VERSION 5.8 ;
BUSBITCHARS "[]" ;

UNITS
  DATABASE MICRONS 2000 ;
END UNITS

PROPERTYDEFINITIONS
  MACRO expanded_util REAL ;
END PROPERTYDEFINITIONS

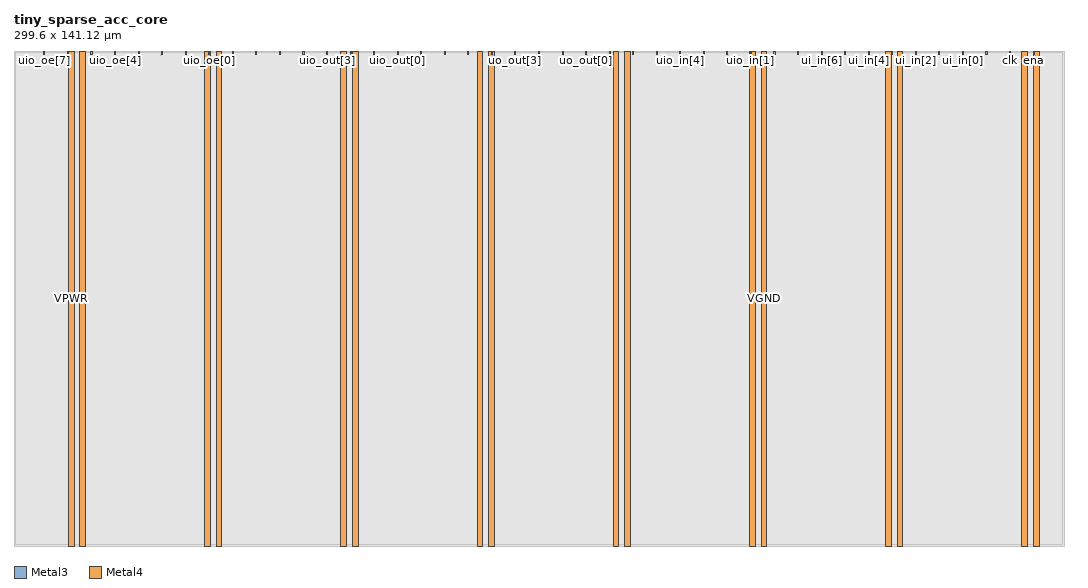
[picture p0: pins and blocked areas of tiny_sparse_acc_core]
MACRO tiny_sparse_acc_core
  CLASS BLOCK ;
  ORIGIN 0 0 ;
  SIZE 299.6 BY 141.12 ;
  SYMMETRY X Y ;
  PIN ui_in[7]
    DIRECTION INPUT ;
    USE SIGNAL ;
    PORT
      LAYER Metal3 ;
        RECT 223.57 140.12 223.87 141.12 ;
    END
  END ui_in[7]
  PIN ui_in[6]
    DIRECTION INPUT ;
    USE SIGNAL ;
    PORT
      LAYER Metal3 ;
        RECT 230.29 140.12 230.59 141.12 ;
    END
  END ui_in[6]
  PIN ui_in[5]
    DIRECTION INPUT ;
    USE SIGNAL ;
    PORT
      LAYER Metal3 ;
        RECT 237.01 140.12 237.31 141.12 ;
    END
  END ui_in[5]
  PIN ui_in[4]
    DIRECTION INPUT ;
    USE SIGNAL ;
    PORT
      LAYER Metal3 ;
        RECT 243.73 140.12 244.03 141.12 ;
    END
  END ui_in[4]
  PIN ui_in[3]
    DIRECTION INPUT ;
    USE SIGNAL ;
    PORT
      LAYER Metal3 ;
        RECT 250.45 140.12 250.75 141.12 ;
    END
  END ui_in[3]
  PIN ui_in[2]
    DIRECTION INPUT ;
    USE SIGNAL ;
    PORT
      LAYER Metal3 ;
        RECT 257.17 140.12 257.47 141.12 ;
    END
  END ui_in[2]
  PIN ui_in[1]
    DIRECTION INPUT ;
    USE SIGNAL ;
    PORT
      LAYER Metal3 ;
        RECT 263.89 140.12 264.19 141.12 ;
    END
  END ui_in[1]
  PIN ui_in[0]
    DIRECTION INPUT ;
    USE SIGNAL ;
    PORT
      LAYER Metal3 ;
        RECT 270.61 140.12 270.91 141.12 ;
    END
  END ui_in[0]
  PIN uo_out[7]
    DIRECTION OUTPUT ;
    USE SIGNAL ;
    PORT
      LAYER Metal3 ;
        RECT 116.05 140.12 116.35 141.12 ;
    END
  END uo_out[7]
  PIN uo_out[6]
    DIRECTION OUTPUT ;
    USE SIGNAL ;
    PORT
      LAYER Metal3 ;
        RECT 122.77 140.12 123.07 141.12 ;
    END
  END uo_out[6]
  PIN uo_out[5]
    DIRECTION OUTPUT ;
    USE SIGNAL ;
    PORT
      LAYER Metal3 ;
        RECT 129.49 140.12 129.79 141.12 ;
    END
  END uo_out[5]
  PIN uo_out[4]
    DIRECTION OUTPUT ;
    USE SIGNAL ;
    PORT
      LAYER Metal3 ;
        RECT 136.21 140.12 136.51 141.12 ;
    END
  END uo_out[4]
  PIN uo_out[3]
    DIRECTION OUTPUT ;
    USE SIGNAL ;
    PORT
      LAYER Metal3 ;
        RECT 142.93 140.12 143.23 141.12 ;
    END
  END uo_out[3]
  PIN uo_out[2]
    DIRECTION OUTPUT ;
    USE SIGNAL ;
    PORT
      LAYER Metal3 ;
        RECT 149.65 140.12 149.95 141.12 ;
    END
  END uo_out[2]
  PIN uo_out[1]
    DIRECTION OUTPUT ;
    USE SIGNAL ;
    PORT
      LAYER Metal3 ;
        RECT 156.37 140.12 156.67 141.12 ;
    END
  END uo_out[1]
  PIN uo_out[0]
    DIRECTION OUTPUT ;
    USE SIGNAL ;
    PORT
      LAYER Metal3 ;
        RECT 163.09 140.12 163.39 141.12 ;
    END
  END uo_out[0]
  PIN uio_in[7]
    DIRECTION INPUT ;
    USE SIGNAL ;
    PORT
      LAYER Metal3 ;
        RECT 169.81 140.12 170.11 141.12 ;
    END
  END uio_in[7]
  PIN uio_in[6]
    DIRECTION INPUT ;
    USE SIGNAL ;
    PORT
      LAYER Metal3 ;
        RECT 176.53 140.12 176.83 141.12 ;
    END
  END uio_in[6]
  PIN uio_in[5]
    DIRECTION INPUT ;
    USE SIGNAL ;
    PORT
      LAYER Metal3 ;
        RECT 183.25 140.12 183.55 141.12 ;
    END
  END uio_in[5]
  PIN uio_in[4]
    DIRECTION INPUT ;
    USE SIGNAL ;
    PORT
      LAYER Metal3 ;
        RECT 189.97 140.12 190.27 141.12 ;
    END
  END uio_in[4]
  PIN uio_in[3]
    DIRECTION INPUT ;
    USE SIGNAL ;
    PORT
      LAYER Metal3 ;
        RECT 196.69 140.12 196.99 141.12 ;
    END
  END uio_in[3]
  PIN uio_in[2]
    DIRECTION INPUT ;
    USE SIGNAL ;
    PORT
      LAYER Metal3 ;
        RECT 203.41 140.12 203.71 141.12 ;
    END
  END uio_in[2]
  PIN uio_in[1]
    DIRECTION INPUT ;
    USE SIGNAL ;
    PORT
      LAYER Metal3 ;
        RECT 210.13 140.12 210.43 141.12 ;
    END
  END uio_in[1]
  PIN uio_in[0]
    DIRECTION INPUT ;
    USE SIGNAL ;
    PORT
      LAYER Metal3 ;
        RECT 216.85 140.12 217.15 141.12 ;
    END
  END uio_in[0]
  PIN uio_out[7]
    DIRECTION OUTPUT ;
    USE SIGNAL ;
    PORT
      LAYER Metal3 ;
        RECT 62.29 140.12 62.59 141.12 ;
    END
  END uio_out[7]
  PIN uio_out[6]
    DIRECTION OUTPUT ;
    USE SIGNAL ;
    PORT
      LAYER Metal3 ;
        RECT 69.01 140.12 69.31 141.12 ;
    END
  END uio_out[6]
  PIN uio_out[5]
    DIRECTION OUTPUT ;
    USE SIGNAL ;
    PORT
      LAYER Metal3 ;
        RECT 75.73 140.12 76.03 141.12 ;
    END
  END uio_out[5]
  PIN uio_out[4]
    DIRECTION OUTPUT ;
    USE SIGNAL ;
    PORT
      LAYER Metal3 ;
        RECT 82.45 140.12 82.75 141.12 ;
    END
  END uio_out[4]
  PIN uio_out[3]
    DIRECTION OUTPUT ;
    USE SIGNAL ;
    PORT
      LAYER Metal3 ;
        RECT 89.17 140.12 89.47 141.12 ;
    END
  END uio_out[3]
  PIN uio_out[2]
    DIRECTION OUTPUT ;
    USE SIGNAL ;
    PORT
      LAYER Metal3 ;
        RECT 95.89 140.12 96.19 141.12 ;
    END
  END uio_out[2]
  PIN uio_out[1]
    DIRECTION OUTPUT ;
    USE SIGNAL ;
    PORT
      LAYER Metal3 ;
        RECT 102.61 140.12 102.91 141.12 ;
    END
  END uio_out[1]
  PIN uio_out[0]
    DIRECTION OUTPUT ;
    USE SIGNAL ;
    PORT
      LAYER Metal3 ;
        RECT 109.33 140.12 109.63 141.12 ;
    END
  END uio_out[0]
  PIN uio_oe[7]
    DIRECTION OUTPUT ;
    USE SIGNAL ;
    PORT
      LAYER Metal3 ;
        RECT 8.53 140.12 8.83 141.12 ;
    END
  END uio_oe[7]
  PIN uio_oe[6]
    DIRECTION OUTPUT ;
    USE SIGNAL ;
    PORT
      LAYER Metal3 ;
        RECT 15.25 140.12 15.55 141.12 ;
    END
  END uio_oe[6]
  PIN uio_oe[5]
    DIRECTION OUTPUT ;
    USE SIGNAL ;
    PORT
      LAYER Metal3 ;
        RECT 21.97 140.12 22.27 141.12 ;
    END
  END uio_oe[5]
  PIN uio_oe[4]
    DIRECTION OUTPUT ;
    USE SIGNAL ;
    PORT
      LAYER Metal3 ;
        RECT 28.69 140.12 28.99 141.12 ;
    END
  END uio_oe[4]
  PIN uio_oe[3]
    DIRECTION OUTPUT ;
    USE SIGNAL ;
    PORT
      LAYER Metal3 ;
        RECT 35.41 140.12 35.71 141.12 ;
    END
  END uio_oe[3]
  PIN uio_oe[2]
    DIRECTION OUTPUT ;
    USE SIGNAL ;
    PORT
      LAYER Metal3 ;
        RECT 42.13 140.12 42.43 141.12 ;
    END
  END uio_oe[2]
  PIN uio_oe[1]
    DIRECTION OUTPUT ;
    USE SIGNAL ;
    PORT
      LAYER Metal3 ;
        RECT 48.85 140.12 49.15 141.12 ;
    END
  END uio_oe[1]
  PIN uio_oe[0]
    DIRECTION OUTPUT ;
    USE SIGNAL ;
    PORT
      LAYER Metal3 ;
        RECT 55.57 140.12 55.87 141.12 ;
    END
  END uio_oe[0]
  PIN ena
    DIRECTION INPUT ;
    USE SIGNAL ;
    PORT
      LAYER Metal3 ;
        RECT 290.77 140.12 291.07 141.12 ;
    END
  END ena
  PIN clk
    DIRECTION INPUT ;
    USE CLOCK ;
    PORT
      LAYER Metal3 ;
        RECT 284.05 140.12 284.35 141.12 ;
    END
  END clk
  PIN rst_n
    DIRECTION INPUT ;
    USE SIGNAL ;
    PORT
      LAYER Metal3 ;
        RECT 277.33 140.12 277.63 141.12 ;
    END
  END rst_n
  PIN VPWR
    DIRECTION INPUT ;
    USE POWER ;
    PORT
      LAYER Metal4 ;
        RECT 15.52 0 17.12 141.12 ;
        RECT 54.39 0 55.99 141.12 ;
        RECT 93.26 0 94.86 141.12 ;
        RECT 132.13 0 133.73 141.12 ;
        RECT 171 0 172.6 141.12 ;
        RECT 209.87 0 211.47 141.12 ;
        RECT 248.74 0 250.34 141.12 ;
        RECT 287.61 0 289.21 141.12 ;
    END
  END VPWR
  PIN VGND
    DIRECTION INPUT ;
    USE GROUND ;
    PORT
      LAYER Metal4 ;
        RECT 18.82 0 20.42 141.12 ;
        RECT 57.69 0 59.29 141.12 ;
        RECT 96.56 0 98.16 141.12 ;
        RECT 135.43 0 137.03 141.12 ;
        RECT 174.3 0 175.9 141.12 ;
        RECT 213.17 0 214.77 141.12 ;
        RECT 252.04 0 253.64 141.12 ;
        RECT 290.91 0 292.51 141.12 ;
    END
  END VGND
  OBS
    LAYER Metal1 SPACING 0 ;
      RECT 0 0 299.6 141.12 ;
    LAYER Metal2 SPACING 0 ;
      RECT 0 0 299.6 141.12 ;
    LAYER Metal3 SPACING 0 ;
      RECT 0 0 299.6 140.12 ;
      RECT 0 140.12 8.53 141.12 ;
      RECT 8.83 140.12 15.25 141.12 ;
      RECT 15.55 140.12 21.97 141.12 ;
      RECT 22.27 140.12 28.69 141.12 ;
      RECT 28.99 140.12 35.41 141.12 ;
      RECT 35.71 140.12 42.13 141.12 ;
      RECT 42.43 140.12 48.85 141.12 ;
      RECT 49.15 140.12 55.57 141.12 ;
      RECT 55.87 140.12 62.29 141.12 ;
      RECT 62.59 140.12 69.01 141.12 ;
      RECT 69.31 140.12 75.73 141.12 ;
      RECT 76.03 140.12 82.45 141.12 ;
      RECT 82.75 140.12 89.17 141.12 ;
      RECT 89.47 140.12 95.89 141.12 ;
      RECT 96.19 140.12 102.61 141.12 ;
      RECT 102.91 140.12 109.33 141.12 ;
      RECT 109.63 140.12 116.05 141.12 ;
      RECT 116.35 140.12 122.77 141.12 ;
      RECT 123.07 140.12 129.49 141.12 ;
      RECT 129.79 140.12 136.21 141.12 ;
      RECT 136.51 140.12 142.93 141.12 ;
      RECT 143.23 140.12 149.65 141.12 ;
      RECT 149.95 140.12 156.37 141.12 ;
      RECT 156.67 140.12 163.09 141.12 ;
      RECT 163.39 140.12 169.81 141.12 ;
      RECT 170.11 140.12 176.53 141.12 ;
      RECT 176.83 140.12 183.25 141.12 ;
      RECT 183.55 140.12 189.97 141.12 ;
      RECT 190.27 140.12 196.69 141.12 ;
      RECT 196.99 140.12 203.41 141.12 ;
      RECT 203.71 140.12 210.13 141.12 ;
      RECT 210.43 140.12 216.85 141.12 ;
      RECT 217.15 140.12 223.57 141.12 ;
      RECT 223.87 140.12 230.29 141.12 ;
      RECT 230.59 140.12 237.01 141.12 ;
      RECT 237.31 140.12 243.73 141.12 ;
      RECT 244.03 140.12 250.45 141.12 ;
      RECT 250.75 140.12 257.17 141.12 ;
      RECT 257.47 140.12 263.89 141.12 ;
      RECT 264.19 140.12 270.61 141.12 ;
      RECT 270.91 140.12 277.33 141.12 ;
      RECT 277.63 140.12 284.05 141.12 ;
      RECT 284.35 140.12 290.77 141.12 ;
      RECT 291.07 140.12 299.6 141.12 ;
    LAYER Metal4 SPACING 0 ;
      RECT 289.21 140.12 290.91 141.12 ;
      RECT 292.51 140.12 299.6 141.12 ;
      RECT 0 0 15.52 141.12 ;
      RECT 17.12 140.12 18.82 141.12 ;
      RECT 20.42 140.12 54.39 141.12 ;
      RECT 55.99 140.12 57.69 141.12 ;
      RECT 59.29 140.12 93.26 141.12 ;
      RECT 94.86 140.12 96.56 141.12 ;
      RECT 98.16 140.12 132.13 141.12 ;
      RECT 133.73 140.12 135.43 141.12 ;
      RECT 137.03 140.12 171 141.12 ;
      RECT 172.6 140.12 174.3 141.12 ;
      RECT 175.9 140.12 209.87 141.12 ;
      RECT 211.47 140.12 213.17 141.12 ;
      RECT 214.77 140.12 248.74 141.12 ;
      RECT 250.34 140.12 252.04 141.12 ;
      RECT 253.64 140.12 287.61 141.12 ;
      RECT 17.12 0 18.82 140.12 ;
      RECT 20.42 0 54.39 140.12 ;
      RECT 55.99 0 57.69 140.12 ;
      RECT 59.29 0 93.26 140.12 ;
      RECT 94.86 0 96.56 140.12 ;
      RECT 98.16 0 132.13 140.12 ;
      RECT 133.73 0 135.43 140.12 ;
      RECT 137.03 0 171 140.12 ;
      RECT 172.6 0 174.3 140.12 ;
      RECT 175.9 0 209.87 140.12 ;
      RECT 211.47 0 213.17 140.12 ;
      RECT 214.77 0 248.74 140.12 ;
      RECT 250.34 0 252.04 140.12 ;
      RECT 253.64 0 287.61 140.12 ;
      RECT 289.21 0 290.91 140.12 ;
      RECT 292.51 0 299.6 140.12 ;
    LAYER Metal3 ;
      RECT 0.3 0.3 299.3 139.82 ;
      RECT 0.3 139.82 8.23 140.82 ;
      RECT 9.13 139.82 14.95 140.82 ;
      RECT 15.85 139.82 21.67 140.82 ;
      RECT 22.57 139.82 28.39 140.82 ;
      RECT 29.29 139.82 35.11 140.82 ;
      RECT 36.01 139.82 41.83 140.82 ;
      RECT 42.73 139.82 48.55 140.82 ;
      RECT 49.45 139.82 55.27 140.82 ;
      RECT 56.17 139.82 61.99 140.82 ;
      RECT 62.89 139.82 68.71 140.82 ;
      RECT 69.61 139.82 75.43 140.82 ;
      RECT 76.33 139.82 82.15 140.82 ;
      RECT 83.05 139.82 88.87 140.82 ;
      RECT 89.77 139.82 95.59 140.82 ;
      RECT 96.49 139.82 102.31 140.82 ;
      RECT 103.21 139.82 109.03 140.82 ;
      RECT 109.93 139.82 115.75 140.82 ;
      RECT 116.65 139.82 122.47 140.82 ;
      RECT 123.37 139.82 129.19 140.82 ;
      RECT 130.09 139.82 135.91 140.82 ;
      RECT 136.81 139.82 142.63 140.82 ;
      RECT 143.53 139.82 149.35 140.82 ;
      RECT 150.25 139.82 156.07 140.82 ;
      RECT 156.97 139.82 162.79 140.82 ;
      RECT 163.69 139.82 169.51 140.82 ;
      RECT 170.41 139.82 176.23 140.82 ;
      RECT 177.13 139.82 182.95 140.82 ;
      RECT 183.85 139.82 189.67 140.82 ;
      RECT 190.57 139.82 196.39 140.82 ;
      RECT 197.29 139.82 203.11 140.82 ;
      RECT 204.01 139.82 209.83 140.82 ;
      RECT 210.73 139.82 216.55 140.82 ;
      RECT 217.45 139.82 223.27 140.82 ;
      RECT 224.17 139.82 229.99 140.82 ;
      RECT 230.89 139.82 236.71 140.82 ;
      RECT 237.61 139.82 243.43 140.82 ;
      RECT 244.33 139.82 250.15 140.82 ;
      RECT 251.05 139.82 256.87 140.82 ;
      RECT 257.77 139.82 263.59 140.82 ;
      RECT 264.49 139.82 270.31 140.82 ;
      RECT 271.21 139.82 277.03 140.82 ;
      RECT 277.93 139.82 283.75 140.82 ;
      RECT 284.65 139.82 290.47 140.82 ;
      RECT 291.37 139.82 299.3 140.82 ;
    LAYER Metal4 ;
      RECT 289.51 139.82 290.61 140.82 ;
      RECT 292.81 139.82 299.3 140.82 ;
      RECT 0.3 0.3 15.22 1.3 ;
      RECT 0.3 1.3 15.52 139.82 ;
      RECT 0.3 139.82 15.22 140.82 ;
      RECT 17.42 139.82 18.52 140.82 ;
      RECT 20.72 139.82 54.09 140.82 ;
      RECT 56.29 139.82 57.39 140.82 ;
      RECT 59.59 139.82 92.96 140.82 ;
      RECT 95.16 139.82 96.26 140.82 ;
      RECT 98.46 139.82 131.83 140.82 ;
      RECT 134.03 139.82 135.13 140.82 ;
      RECT 137.33 139.82 170.7 140.82 ;
      RECT 172.9 139.82 174 140.82 ;
      RECT 176.2 139.82 209.57 140.82 ;
      RECT 211.77 139.82 212.87 140.82 ;
      RECT 215.07 139.82 248.44 140.82 ;
      RECT 250.64 139.82 251.74 140.82 ;
      RECT 253.94 139.82 287.31 140.82 ;
      RECT 17.42 0.3 18.52 1.3 ;
      RECT 17.12 1.3 18.82 139.82 ;
      RECT 20.72 0.3 54.09 1.3 ;
      RECT 20.42 1.3 54.39 139.82 ;
      RECT 56.29 0.3 57.39 1.3 ;
      RECT 55.99 1.3 57.69 139.82 ;
      RECT 59.59 0.3 92.96 1.3 ;
      RECT 59.29 1.3 93.26 139.82 ;
      RECT 95.16 0.3 96.26 1.3 ;
      RECT 94.86 1.3 96.56 139.82 ;
      RECT 98.46 0.3 131.83 1.3 ;
      RECT 98.16 1.3 132.13 139.82 ;
      RECT 134.03 0.3 135.13 1.3 ;
      RECT 133.73 1.3 135.43 139.82 ;
      RECT 137.33 0.3 170.7 1.3 ;
      RECT 137.03 1.3 171 139.82 ;
      RECT 172.9 0.3 174 1.3 ;
      RECT 172.6 1.3 174.3 139.82 ;
      RECT 176.2 0.3 209.57 1.3 ;
      RECT 175.9 1.3 209.87 139.82 ;
      RECT 211.77 0.3 212.87 1.3 ;
      RECT 211.47 1.3 213.17 139.82 ;
      RECT 215.07 0.3 248.44 1.3 ;
      RECT 214.77 1.3 248.74 139.82 ;
      RECT 250.64 0.3 251.74 1.3 ;
      RECT 250.34 1.3 252.04 139.82 ;
      RECT 253.94 0.3 287.31 1.3 ;
      RECT 253.64 1.3 287.61 139.82 ;
      RECT 289.51 0.3 290.61 1.3 ;
      RECT 289.21 1.3 290.91 139.82 ;
      RECT 292.81 0.3 299.3 1.3 ;
      RECT 292.51 1.3 299.3 139.82 ;
    LAYER Metal1 ;
      RECT 0.3 0.3 299.3 140.82 ;
    LAYER Metal2 ;
      RECT 0.3 0.3 299.3 140.82 ;
    LAYER Via2 ;
      RECT 149.39 140.43 149.65 140.69 ;
      RECT 82.19 140.43 82.45 140.69 ;
      RECT 76.03 140.43 76.29 140.69 ;
      RECT 203.71 139.87 203.97 140.13 ;
      RECT 156.67 139.87 156.93 140.13 ;
      RECT 41.87 139.87 42.13 140.13 ;
    LAYER Via3 ;
      RECT 277.07 140.43 277.33 140.69 ;
      RECT 129.79 140.43 130.05 140.69 ;
      RECT 122.51 140.43 122.77 140.69 ;
      RECT 109.07 140.43 109.33 140.69 ;
      RECT 88.91 140.43 89.17 140.69 ;
      RECT 163.39 139.87 163.65 140.13 ;
  END
  PROPERTY expanded_util 0.887 ;
END tiny_sparse_acc_core

END LIBRARY
